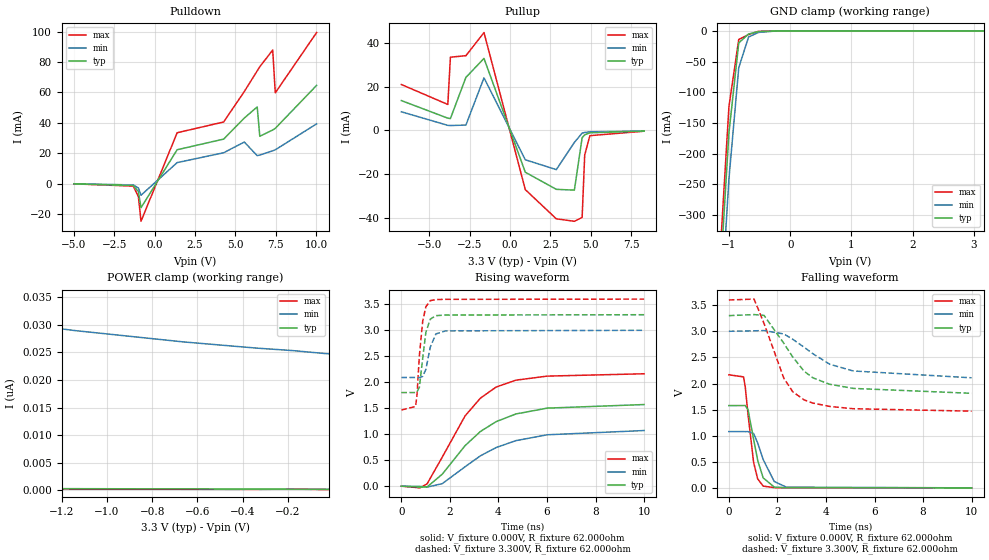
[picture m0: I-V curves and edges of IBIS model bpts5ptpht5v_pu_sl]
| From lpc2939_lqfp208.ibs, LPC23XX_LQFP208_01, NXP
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| |   Rev 0.20 IBIS Model Design Automation Generation   |
| |   N O N - S I L I C O N   C O R R E L A T E D   |
| |   This IBIS [Model] is pre-Beta tactical support   |
| |  Note: this IBIS [Model] contains clamp curves generated   |
| |   through simulation which should not be relied upon   |
| Pccmos14 hliolib_nlm 4.0.1
|   0.18 um 3.3V pad library
|   six level metal
|   dual oxide
|   single threshold voltage
|   nominal line mixed supply
|   parasitic extracted netlists
| Process block c14
| bpts5ptpht5v
|   Bidirectional Pad 3v3
|   3state Output
|   Plain Input
|   1ns Slew Rate control
|   CMOS
|   Programmable between
|   - (p1=0, p2=1) plain input
|   - (p1=0, p2=0) with Pull Up
|   - (p1=1, p2=1) with Pull Down
|   - (p1=1, p2=0) with Repeater
|   Characterized at Core 1.8V and I/O 3.3V
| Pull Up Mode (p1=0, p2=0)
[Model]   bpts5ptpht5v_pu_sl | of bpts5ptpht5v
Model_type   I/O
Polarity   Non-Inverting
Enable   Active-Low
|  Reciever Thresholds
Vinl   = 0.99V
Vinh   = 2.31V
| AC Test Load Conditions
Vref   = 0
Cref   = 1.2e-11
Rref   = 1000000000
Vmeas   = 1.65
| [Process Range]   typical   min   max
| C_comp edge width   400.000ps   400.000ps   400.000ps
| C_comp Tstrobe   40.000fs   40.000fs   40.000fs
C_comp   2.521pF   2.387pF   2.657pF
[Temperature Range]   25   125   -40
[Voltage Range]   3.30V   3.00V   3.60V
[GND Clamp Reference]   0.00V   0.00V   0.00V
[Pulldown Reference]   0.00V   0.00V   0.00V
[POWER Clamp Reference]   3.30V   3.00V   3.60V
[Pullup Reference]   3.30V   3.00V   3.60V
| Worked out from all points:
|   slope of the pulldown table from 0 to 0.495 V, typ, clamps not added: 46.5 ohm
|   slope of the pullup table from 0 to 0.495 V, typ, clamps not added: 41.9 ohm
|   GND clamp passes 1 mA (typ) near -0.48 V on its own axis
|   rising waveform, V_fixture 0.000V, R_fixture 62.000ohm: 20-80 % time 2.15ns typ, 2.37ns min, 1.79ns max; typ from 0.001 V to 1.57 V
|   falling waveform, V_fixture 0.000V, R_fixture 62.000ohm: 20-80 % time 410ps typ, 537ps min, 319ps max; typ from 1.58 V to 0.001 V
|   rising waveform, V_fixture 3.300V, R_fixture 62.000ohm: 20-80 % time 223ps typ, 260ps min, 214ps max; typ from 1.8 V to 3.3 V
|   falling waveform, V_fixture 3.300V, R_fixture 62.000ohm: 20-80 % time 1.52ns typ, 1.95ns min, 1.1ns max; typ from 3.3 V to 1.81 V
[GND Clamp]
| ref voltage   0.00V   0.00V   0.00V
|   Voltage   I(typ)   I(min)   I(max)
-5V       -7.933A    -7.953A    -7.929A
-1.16V    -429.6mA   -501mA     -389.4mA
-1V       -166mA     -240.8mA   -123.1mA
-840mV    -19.71mA   -60.08mA   -14.11mA
-680mV    -5.176mA   -10.17mA   -6.124mA
-520mV    -1.303mA   -2.648mA   -850.4uA
-200mV    -54.41uA   -43.67uA   -84.58uA
3.16V     195.7pA    25.28nA    129.9pA
[Power Clamp]   | Vtable = Vcc - Vpad
| ref voltage   3.30V   3.00V   3.60V
|   Voltage   I(typ)   I(min)   I(max)
-6.74V    1.25nA     124.2nA    594.5pA
-4.66V    764.3pA    69.65nA    461.2pA
-2.42V    442.5pA    37.56nA    320.3pA
-2.26V    425.1pA    36.17nA    310.3pA
-2.1V     408.2pA    34.87nA    300.3pA
-1.78V    376pA      32.56nA    280.3pA
-1.46V    345.7pA    30.59nA    260.3pA
-1.14V    316.9pA    28.91nA    240.4pA
-660mV    276.2pA    26.86nA    210.5pA
-340mV    250.5pA    25.75nA    190.5pA
-180mV    238.9pA    25.3nA     243pA
-20mV     211pA      24.7nA     154.4pA
[Pulldown]
| ref voltage   0.00V   0.00V   0.00V
|   Voltage   I(typ)   I(min)   I(max)
-5V       -187.5uA   -145.7uA   -211.8uA
-1.32V    -1.32mA    -939.4uA   -1.723mA
-1V       -5.322mA   -2.96mA    -8.616mA
-840mV    -15.95mA   -7.733mA   -24.9mA
1.4V      22.26mA    13.79mA    33.48mA
4.28V     29.27mA    20.27mA    40.55mA
5.56V     43.15mA    27.33mA    60.63mA
6.36V     50.49mA    18.36mA    74.24mA
6.52V     31.16mA    18.79mA    76.97mA
7.32V     35.27mA    21.55mA    87.95mA
7.48V     36.36mA    22.22mA    59.78mA
10.04V    64.68mA    39.32mA    99.49mA
[Pullup]   | Vtable = Vcc - Vpad
| ref voltage   3.30V   3.00V   3.60V
|   Voltage   I(typ)   I(min)   I(max)
-6.74V    13.67mA    8.53mA     21.02mA
-3.86V    5.598mA    2.307mA    11.88mA
-3.7V     5.416mA    2.227mA    33.56mA
-2.74V    24.29mA    2.441mA    34.22mA
-1.62V    32.99mA    24.07mA    44.83mA
940mV     -19.18mA   -13.46mA   -27.14mA
2.86V     -27.01mA   -17.98mA   -40.52mA
3.98V     -27.38mA   -5.509mA   -41.66mA
4.46V     -3.36mA    -1.235mA   -39.9mA
4.62V     -2.02mA    -961.4uA   -11.27mA
4.94V     -1.105mA   -662.3uA   -2.417mA
8.3V      -310.5uA   -276uA     -365.2uA
[Ramp]
R_load   = 62.000ohm
|   dV/dt(typ)   dV/dt(min)   dV/dt(max)
dV/dt_r   721.328mV/2.200ns   483.079mV/2.360ns   1.050V/2.035ns
dV/dt_f   674.652mV/1.570ns   397.626mV/1.940ns   1.037V/1.245ns
[Rising Waveform]  | cubic spline decimation from 2001 points
V_fixture   = 0.000V
R_fixture   = 62.000ohm
|   Time   V(typ)   V(min)   V(max)
0s        1.319mV    1.084mV    1.611mV
765ps     -15.73mV   -2.081mV   -30.78mV
1.06ns    -13.54mV   -16.36mV   45.51mV
1.685ns   231.6mV    50.01mV    560.2mV
2.625ns   780.8mV    374.8mV    1.353V
3.255ns   1.053V     584.8mV    1.694V
3.905ns   1.243V     745mV      1.909V
4.72ns    1.391V     877.7mV    2.041V
6.01ns    1.503V     990.3mV    2.119V
10ns      1.572V     1.072V     2.164V
[Falling Waveform]  | cubic spline decimation from 2001 points
V_fixture   = 0.000V
R_fixture   = 62.000ohm
|   Time   V(typ)   V(min)   V(max)
0s        1.577V     1.079V     2.167V
605ps     1.578V     1.079V     2.127V
675ps     1.579V     1.078V     1.941V
790ps     1.498V     1.079V     1.408V
1.02ns    932.9mV    1.043V     489.2mV
1.19ns    524.6mV    858.9mV    171.6mV
1.415ns   192mV      543.6mV    34.84mV
1.87ns    16.32mV    122.6mV    5.179mV
2.37ns    4.054mV    15.26mV    3.258mV
10ns      1.364mV    1.194mV    1.632mV
[Rising Waveform]  | cubic spline decimation from 2001 points
V_fixture   = 3.300V
V_fixture_min = 3.000V
V_fixture_max = 3.600V
R_fixture   = 62.000ohm
|   Time   V(typ)   V(min)   V(max)
0s        1.803V     2.092V     1.467V
585ps     1.803V     2.093V     1.535V
640ps     1.811V     2.093V     1.722V
745ps     1.907V     2.092V     2.525V
880ps     2.464V     2.114V     3.175V
1.01ns    2.96V      2.248V     3.452V
1.19ns    3.214V     2.673V     3.571V
1.425ns   3.282V     2.931V     3.592V
1.82ns    3.294V     2.989V     3.596V
10ns      3.3V       3V         3.6V
[Falling Waveform]  | cubic spline decimation from 2001 points
V_fixture   = 3.300V
V_fixture_min = 3.000V
V_fixture_max = 3.600V
R_fixture   = 62.000ohm
|   Time   V(typ)   V(min)   V(max)
0s        3.3V       3V         3.6V
1.04ns    3.32V      3.009V     3.616V
1.45ns    3.304V     3.014V     3.151V
2.265ns   2.77V      2.949V     2.102V
2.63ns    2.509V     2.848V     1.843V
3.1ns     2.235V     2.695V     1.686V
3.47ns    2.107V     2.568V     1.624V
4.155ns   1.985V     2.369V     1.561V
5.125ns   1.906V     2.24V      1.517V
10ns      1.812V     2.109V     1.47V
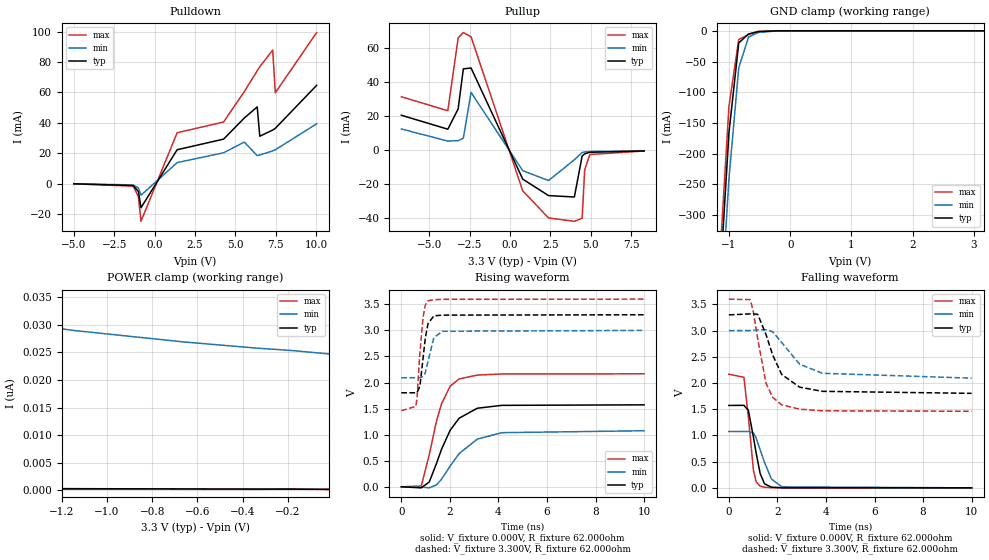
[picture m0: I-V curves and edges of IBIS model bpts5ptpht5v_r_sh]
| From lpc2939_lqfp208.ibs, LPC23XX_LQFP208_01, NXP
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| |   Rev 0.20 IBIS Model Design Automation Generation   |
| |   N O N - S I L I C O N   C O R R E L A T E D   |
| |   This IBIS [Model] is pre-Beta tactical support   |
| |  Note: this IBIS [Model] contains clamp curves generated   |
| |   through simulation which should not be relied upon   |
| Pccmos14 hliolib_nlm 4.0.1
|   0.18 um 3.3V pad library
|   six level metal
|   dual oxide
|   single threshold voltage
|   nominal line mixed supply
|   parasitic extracted netlists
| Process block c14
| bpts5ptpht5v
|   Bidirectional Pad 3v3
|   3state Output
|   Plain Input
|   1ns Slew Rate control
|   CMOS
|   Programmable between
|   - (p1=0, p2=1) plain input
|   - (p1=0, p2=0) with Pull Up
|   - (p1=1, p2=1) with Pull Down
|   - (p1=1, p2=0) with Repeater
|   Characterized at Core 1.8V and I/O 3.3V
| Repeater Mode (p1=1, p2=0)
[Model]   bpts5ptpht5v_r_sh | of bpts5ptpht5v
Model_type   I/O
Polarity   Non-Inverting
Enable   Active-Low
|  Reciever Thresholds
Vinl   = 0.99V
Vinh   = 2.31V
| AC Test Load Conditions
Vref   = 0
Cref   = 1.2e-11
Rref   = 1000000000
Vmeas   = 1.65
| [Process Range]   typical   min   max
| C_comp edge width   400.000ps   400.000ps   400.000ps
| C_comp Tstrobe   40.000fs   40.000fs   40.000fs
C_comp   2.521pF   2.386pF   2.657pF
[Temperature Range]   25   125   -40
[Voltage Range]   3.30V   3.00V   3.60V
[GND Clamp Reference]   0.00V   0.00V   0.00V
[Pulldown Reference]   0.00V   0.00V   0.00V
[POWER Clamp Reference]   3.30V   3.00V   3.60V
[Pullup Reference]   3.30V   3.00V   3.60V
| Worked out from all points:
|   slope of the pulldown table from 0 to 0.495 V, typ, clamps not added: 46.5 ohm
|   slope of the pullup table from 0 to 0.495 V, typ, clamps not added: 41.9 ohm
|   GND clamp passes 1 mA (typ) near -0.48 V on its own axis
|   rising waveform, V_fixture 0.000V, R_fixture 62.000ohm: 20-80 % time 921ps typ, 1.16ns min, 704ps max; typ from 0 V to 1.57 V
|   falling waveform, V_fixture 0.000V, R_fixture 62.000ohm: 20-80 % time 364ps typ, 508ps min, 257ps max; typ from 1.57 V to 0 V
|   rising waveform, V_fixture 3.300V, R_fixture 62.000ohm: 20-80 % time 222ps typ, 261ps min, 203ps max; typ from 1.8 V to 3.3 V
|   falling waveform, V_fixture 3.300V, R_fixture 62.000ohm: 20-80 % time 805ps typ, 1.12ns min, 535ps max; typ from 3.3 V to 1.8 V
[GND Clamp]
| ref voltage   0.00V   0.00V   0.00V
|   Voltage   I(typ)   I(min)   I(max)
-5V       -7.933A    -7.953A    -7.929A
-1.16V    -429.6mA   -501mA     -389.4mA
-1V       -166mA     -240.8mA   -123.1mA
-840mV    -19.71mA   -60.08mA   -14.11mA
-680mV    -5.172mA   -10.16mA   -6.119mA
-520mV    -1.294mA   -2.638mA   -834.5uA
-200mV    -15.34uA   -18.05uA   -23.66uA
3.16V     195.7pA    25.28nA    129.9pA
[Power Clamp]   | Vtable = Vcc - Vpad
| ref voltage   3.30V   3.00V   3.60V
|   Voltage   I(typ)   I(min)   I(max)
-6.74V    1.25nA     124.2nA    594.5pA
-4.66V    764.3pA    69.65nA    461.2pA
-2.42V    442.5pA    37.56nA    320.3pA
-2.26V    425.1pA    36.17nA    310.3pA
-2.1V     408.2pA    34.87nA    300.3pA
-1.78V    376pA      32.56nA    280.3pA
-1.46V    345.7pA    30.59nA    260.3pA
-1.14V    316.9pA    28.91nA    240.4pA
-660mV    276.2pA    26.86nA    210.5pA
-340mV    250.5pA    25.75nA    190.5pA
-180mV    238.9pA    25.3nA     243pA
-20mV     211pA      24.7nA     154.4pA
[Pulldown]
| ref voltage   0.00V   0.00V   0.00V
|   Voltage   I(typ)   I(min)   I(max)
-5V       -187.5uA   -145.7uA   -211.8uA
-1.32V    -1.32mA    -939.4uA   -1.723mA
-1V       -5.322mA   -2.96mA    -8.616mA
-840mV    -15.95mA   -7.733mA   -24.9mA
1.4V      22.26mA    13.79mA    33.48mA
4.28V     29.27mA    20.27mA    40.55mA
5.56V     43.15mA    27.33mA    60.63mA
6.36V     50.49mA    18.36mA    74.24mA
6.52V     31.16mA    18.79mA    76.97mA
7.32V     35.27mA    21.55mA    87.95mA
7.48V     36.36mA    22.22mA    59.78mA
10.04V    64.68mA    39.32mA    99.49mA
[Pullup]   | Vtable = Vcc - Vpad
| ref voltage   3.30V   3.00V   3.60V
|   Voltage   I(typ)   I(min)   I(max)
-6.74V    20.65mA    12.57mA    31.52mA
-3.86V    12.45mA    5.473mA    23.29mA
-3.22V    24.39mA    5.73mA     66.13mA
-2.9V     47.88mA    7.139mA    69.22mA
-2.42V    48.4mA     34.05mA    66.69mA
780mV     -16.88mA   -11.92mA   -23.75mA
2.38V     -26.56mA   -17.72mA   -39.7mA
3.98V     -27.38mA   -5.509mA   -41.66mA
4.46V     -3.36mA    -1.235mA   -39.9mA
4.62V     -2.02mA    -961.4uA   -11.27mA
4.94V     -1.105mA   -662.3uA   -2.417mA
8.3V      -310.5uA   -276uA     -365.2uA
[Ramp]
R_load   = 62.000ohm
|   dV/dt(typ)   dV/dt(min)   dV/dt(max)
dV/dt_r   722.040mV/915.000ps   485.123mV/1.125ns   1.049V/765.000ps
dV/dt_f   678.844mV/810.000ps   404.699mV/1.100ns   1.039V/585.000ps
[Rising Waveform]  | cubic spline decimation from 2001 points
V_fixture   = 0.000V
R_fixture   = 62.000ohm
|   Time   V(typ)   V(min)   V(max)
0s        2.032nV    363.7nV    1.043nV
820ps     -20.77mV   -5.722mV   13.87mV
1.15ns    91.74mV    -19.9mV    616.2mV
1.45ns    450.3mV    36.17mV    1.263V
1.655ns   719.3mV    144.1mV    1.591V
2.01ns    1.084V     396.8mV    1.93V
2.38ns    1.315V     636.8mV    2.069V
3.13ns    1.507V     915.2mV    2.143V
4.14ns    1.562V     1.038V     2.164V
10ns      1.572V     1.075V     2.167V
[Falling Waveform]  | cubic spline decimation from 2001 points
V_fixture   = 0.000V
R_fixture   = 62.000ohm
|   Time   V(typ)   V(min)   V(max)
0s        1.572V     1.075V     2.167V
620ps     1.574V     1.075V     2.11V
805ps     1.479V     1.076V     1.346V
1.015ns   961.7mV    1.047V     329.7mV
1.125ns   663.2mV    950.5mV    116.8mV
1.29ns    274.3mV    727.3mV    32.35mV
1.47ns    76.73mV    483.5mV    11.6mV
1.755ns   12.7mV     169.2mV    3.364mV
2.185ns   2.64mV     19.15mV    1.244mV
10ns      415.3nV    6.218uV    21.27nV
[Rising Waveform]  | cubic spline decimation from 2001 points
V_fixture   = 3.300V
V_fixture_min = 3.000V
V_fixture_max = 3.600V
R_fixture   = 62.000ohm
|   Time   V(typ)   V(min)   V(max)
0s        1.803V     2.092V     1.461V
600ps     1.803V     2.093V     1.543V
650ps     1.812V     2.092V     1.721V
765ps     1.929V     2.092V     2.578V
895ps     2.467V     2.116V     3.244V
985ps     2.845V     2.183V     3.486V
1.1ns     3.131V     2.414V     3.569V
1.34ns    3.279V     2.863V     3.589V
1.695ns   3.293V     2.983V     3.596V
10ns      3.3V       3V         3.6V
[Falling Waveform]  | cubic spline decimation from 2001 points
V_fixture   = 3.300V
V_fixture_min = 3.000V
V_fixture_max = 3.600V
R_fixture   = 62.000ohm
|   Time   V(typ)   V(min)   V(max)
0s        3.3V       3V         3.6V
880ps     3.318V     3.001V     3.59V
995ps     3.32V      3.006V     3.396V
1.19ns    3.309V     3.014V     2.842V
1.53ns    2.926V     3.014V     1.997V
1.805ns   2.536V     2.979V     1.727V
2.175ns   2.164V     2.774V     1.584V
2.915ns   1.921V     2.359V     1.501V
3.855ns   1.841V     2.185V     1.47V
10ns      1.803V     2.093V     1.461V
